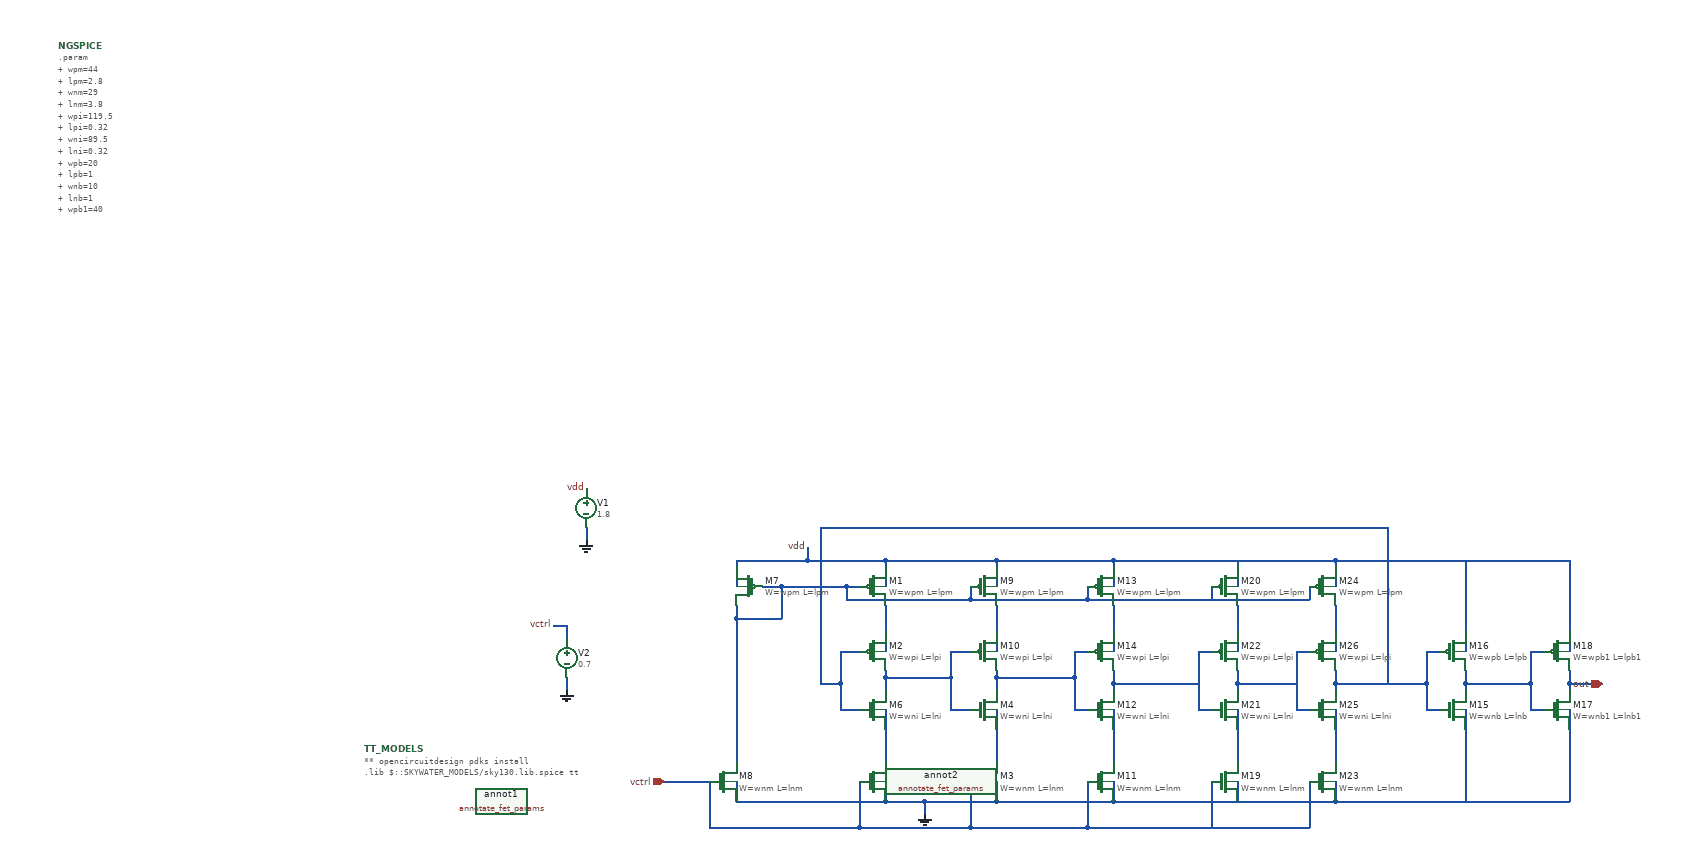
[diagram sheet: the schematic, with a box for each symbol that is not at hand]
v {xschem version=3.4.8RC file_version=1.3}
G {}
K {}
V {}
S {}
F {}
E {}
B 2 770 50 1570 450 {flags=graph
y1=-0.039
y2=1.9
ypos1=0
ypos2=2
divy=5
subdivy=1
unity=1
x1=0
x2=2e-06
divx=5
subdivx=1
xlabmag=1.0
ylabmag=1.0
node=out
color=4
dataset=-1
unitx=1
logx=0
logy=0
hilight_wave=0}
N 480 750 480 770 {lab=#net1}
N 480 640 480 710 {lab=#net2}
N 410 760 410 800 {lab=#net3}
N 410 710 440 710 {lab=#net3}
N 420 610 440 610 {lab=#net4}
N 250 660 320 660 {lab=#net4}
N 320 610 320 660 {lab=#net4}
N 440 910 440 980 {lab=vctrl}
N 210 910 210 980 {lab=vctrl}
N 140 910 210 910 {lab=vctrl}
N 250 910 250 940 {lab=0}
N 250 940 480 940 {lab=0}
N 480 910 480 940 {lab=0}
N 410 800 440 800 {lab=#net3}
N 250 570 250 610 {lab=vdd}
N 360 570 480 570 {lab=vdd}
N 480 570 480 610 {lab=vdd}
N 650 640 650 710 {lab=#net5}
N 610 910 610 980 {lab=vctrl}
N 650 910 650 940 {lab=0}
N 650 570 650 610 {lab=vdd}
N 480 750 580 750 {lab=#net1}
N 580 710 580 750 {lab=#net1}
N 580 710 610 710 {lab=#net1}
N 580 750 580 800 {lab=#net1}
N 580 800 610 800 {lab=#net1}
N 480 570 650 570 {lab=vdd}
N 830 640 830 710 {lab=#net6}
N 790 910 790 980 {lab=vctrl}
N 830 910 830 940 {lab=0}
N 830 570 830 610 {lab=vdd}
N 650 750 770 750 {lab=#net7}
N 770 710 770 750 {lab=#net7}
N 770 710 790 710 {lab=#net7}
N 770 750 770 800 {lab=#net7}
N 770 800 790 800 {lab=#net7}
N 910 760 950 760 {lab=#net8}
N 380 520 380 760 {lab=#net3}
N 380 760 410 760 {lab=#net3}
N 650 940 830 940 {lab=0}
N 610 980 790 980 {lab=vctrl}
N 250 660 250 880 {lab=#net4}
N 360 550 360 570 {lab=vdd}
N 650 570 830 570 {lab=vdd}
N 480 800 480 890 {lab=#net9}
N 20 520 20 540 {lab=0}
N -30 670 -10 670 {lab=vctrl}
N -10 670 -10 690 {lab=vctrl}
N -10 750 -10 770 {lab=0}
N 420 610 420 630 {lab=#net4}
N 420 630 610 630 {lab=#net4}
N 610 610 610 630 {lab=#net4}
N 610 630 790 630 {lab=#net4}
N 790 610 790 630 {lab=#net4}
N 650 750 650 770 {lab=#net7}
N 650 800 650 890 {lab=#net10}
N 830 760 830 770 {lab=#net8}
N 830 800 830 890 {lab=#net11}
N 830 570 1010 570 {lab=vdd}
N 380 520 910 520 {lab=#net3}
N 1010 570 1170 570 {lab=vdd}
N 1010 940 1170 940 {lab=0}
N 250 640 250 660 {lab=#net4}
N 290 610 320 610 {lab=#net4}
N 210 980 440 980 {lab=vctrl}
N 250 570 360 570 {lab=vdd}
N 440 980 610 980 {lab=vctrl}
N 540 940 650 940 {lab=0}
N 480 740 480 750 {lab=#net1}
N 650 740 650 750 {lab=#net7}
N 830 740 830 760 {lab=#net8}
N 410 710 410 760 {lab=#net3}
N 480 940 540 940 {lab=0}
N 320 610 420 610 {lab=#net4}
N 830 760 910 760 {lab=#net8}
N 830 940 1010 940 {lab=0}
N 540 940 540 960 {lab=0}
N 1310 710 1310 760 {lab=#net3}
N 1310 710 1330 710 {lab=#net3}
N 1310 760 1310 800 {lab=#net3}
N 1310 800 1330 800 {lab=#net3}
N 1370 760 1370 770 {lab=#net12}
N 1370 760 1470 760 {lab=#net12}
N 1470 710 1470 760 {lab=#net12}
N 1470 710 1490 710 {lab=#net12}
N 1470 760 1470 800 {lab=#net12}
N 1470 800 1490 800 {lab=#net12}
N 1530 760 1530 770 {lab=out}
N 1530 760 1580 760 {lab=out}
N 1370 740 1370 760 {lab=#net12}
N 1530 740 1530 760 {lab=out}
N 1020 640 1020 710 {lab=#net13}
N 980 910 980 980 {lab=vctrl}
N 1020 910 1020 940 {lab=0}
N 1020 570 1020 610 {lab=vdd}
N 960 710 960 750 {lab=#net8}
N 960 710 980 710 {lab=#net8}
N 960 750 960 800 {lab=#net8}
N 960 800 980 800 {lab=#net8}
N 980 610 980 630 {lab=#net4}
N 1020 760 1020 770 {lab=#net14}
N 1020 800 1020 890 {lab=#net15}
N 1020 740 1020 760 {lab=#net14}
N 1170 640 1170 710 {lab=#net16}
N 1130 910 1130 980 {lab=vctrl}
N 1170 910 1170 940 {lab=0}
N 1170 570 1170 610 {lab=vdd}
N 1110 710 1110 750 {lab=#net14}
N 1110 710 1130 710 {lab=#net14}
N 1110 750 1110 800 {lab=#net14}
N 1110 800 1130 800 {lab=#net14}
N 1130 610 1130 630 {lab=#net4}
N 1170 760 1170 770 {lab=#net3}
N 1170 800 1170 890 {lab=#net17}
N 1170 740 1170 760 {lab=#net3}
N 1170 760 1310 760 {lab=#net3}
N 1170 570 1530 570 {lab=vdd}
N 1530 570 1530 680 {lab=vdd}
N 1370 570 1370 680 {lab=vdd}
N 1370 680 1370 710 {lab=vdd}
N 1530 680 1530 710 {lab=vdd}
N 1370 800 1370 830 {lab=0}
N 1530 800 1530 830 {lab=0}
N 1170 940 1530 940 {lab=0}
N 1530 830 1530 940 {lab=0}
N 1370 830 1370 940 {lab=0}
N 790 980 1130 980 {lab=vctrl}
N 790 630 1130 630 {lab=#net4}
N 950 760 960 760 {lab=#net8}
N 1020 760 1110 760 {lab=#net14}
N 1250 520 1250 760 {lab=#net3}
N 910 520 1250 520 {lab=#net3}
C {sky130_fd_pr/pfet_01v8.sym} 270 610 0 1 {name=M7
W="wpm"
L="lpm"
nf=1
mult=1
ad="expr('int((@nf + 1)/2) * @W / @nf * 0.29')"
pd="expr('2*int((@nf + 1)/2) * (@W / @nf + 0.29)')"
as="expr('int((@nf + 2)/2) * @W / @nf * 0.29')"
ps="expr('2*int((@nf + 2)/2) * (@W / @nf + 0.29)')"
nrd="expr('0.29 / @W ')" nrs="expr('0.29 / @W ')"
sa=0 sb=0 sd=0
model=pfet_01v8
spiceprefix=X
}
C {sky130_fd_pr/nfet_01v8.sym} 230 910 0 0 {name=M8
W="wnm"
L="lnm"
nf=1 
mult=1
ad="expr('int((@nf + 1)/2) * @W / @nf * 0.29')"
pd="expr('2*int((@nf + 1)/2) * (@W / @nf + 0.29)')"
as="expr('int((@nf + 2)/2) * @W / @nf * 0.29')"
ps="expr('2*int((@nf + 2)/2) * (@W / @nf + 0.29)')"
nrd="expr('0.29 / @W ')" nrs="expr('0.29 / @W ')"
sa=0 sb=0 sd=0
model=nfet_01v8
spiceprefix=X
}
C {sky130_fd_pr/nfet_01v8.sym} 460 910 0 0 {name=M5
W="wnm"
L="lnm"
nf=1 
mult=1
ad="expr('int((@nf + 1)/2) * @W / @nf * 0.29')"
pd="expr('2*int((@nf + 1)/2) * (@W / @nf + 0.29)')"
as="expr('int((@nf + 2)/2) * @W / @nf * 0.29')"
ps="expr('2*int((@nf + 2)/2) * (@W / @nf + 0.29)')"
nrd="expr('0.29 / @W ')" nrs="expr('0.29 / @W ')"
sa=0 sb=0 sd=0
model=nfet_01v8
spiceprefix=X
}
C {sky130_fd_pr/nfet_01v8.sym} 460 800 0 0 {name=M6
W="wni"
L="lni"
nf=1 
mult=1
ad="expr('int((@nf + 1)/2) * @W / @nf * 0.29')"
pd="expr('2*int((@nf + 1)/2) * (@W / @nf + 0.29)')"
as="expr('int((@nf + 2)/2) * @W / @nf * 0.29')"
ps="expr('2*int((@nf + 2)/2) * (@W / @nf + 0.29)')"
nrd="expr('0.29 / @W ')" nrs="expr('0.29 / @W ')"
sa=0 sb=0 sd=0
model=nfet_01v8
spiceprefix=X
}
C {sky130_fd_pr/pfet_01v8.sym} 460 610 0 0 {name=M1
W="wpm"
L="lpm"
nf=1
mult=1
ad="expr('int((@nf + 1)/2) * @W / @nf * 0.29')"
pd="expr('2*int((@nf + 1)/2) * (@W / @nf + 0.29)')"
as="expr('int((@nf + 2)/2) * @W / @nf * 0.29')"
ps="expr('2*int((@nf + 2)/2) * (@W / @nf + 0.29)')"
nrd="expr('0.29 / @W ')" nrs="expr('0.29 / @W ')"
sa=0 sb=0 sd=0
model=pfet_01v8
spiceprefix=X
}
C {sky130_fd_pr/pfet_01v8.sym} 460 710 0 0 {name=M2
W="wpi"
L="lpi"
nf=1
mult=1
ad="expr('int((@nf + 1)/2) * @W / @nf * 0.29')"
pd="expr('2*int((@nf + 1)/2) * (@W / @nf + 0.29)')"
as="expr('int((@nf + 2)/2) * @W / @nf * 0.29')"
ps="expr('2*int((@nf + 2)/2) * (@W / @nf + 0.29)')"
nrd="expr('0.29 / @W ')" nrs="expr('0.29 / @W ')"
sa=0 sb=0 sd=0
model=pfet_01v8
spiceprefix=X
}
C {sky130_fd_pr/nfet_01v8.sym} 630 910 0 0 {name=M3
W="wnm"
L="lnm"
nf=1 
mult=1
ad="expr('int((@nf + 1)/2) * @W / @nf * 0.29')"
pd="expr('2*int((@nf + 1)/2) * (@W / @nf + 0.29)')"
as="expr('int((@nf + 2)/2) * @W / @nf * 0.29')"
ps="expr('2*int((@nf + 2)/2) * (@W / @nf + 0.29)')"
nrd="expr('0.29 / @W ')" nrs="expr('0.29 / @W ')"
sa=0 sb=0 sd=0
model=nfet_01v8
spiceprefix=X
}
C {sky130_fd_pr/pfet_01v8.sym} 630 610 0 0 {name=M9
W="wpm"
L="lpm"
nf=1
mult=1
ad="expr('int((@nf + 1)/2) * @W / @nf * 0.29')"
pd="expr('2*int((@nf + 1)/2) * (@W / @nf + 0.29)')"
as="expr('int((@nf + 2)/2) * @W / @nf * 0.29')"
ps="expr('2*int((@nf + 2)/2) * (@W / @nf + 0.29)')"
nrd="expr('0.29 / @W ')" nrs="expr('0.29 / @W ')"
sa=0 sb=0 sd=0
model=pfet_01v8
spiceprefix=X
}
C {sky130_fd_pr/nfet_01v8.sym} 810 910 0 0 {name=M11
W="wnm"
L="lnm"
nf=1 
mult=1
ad="expr('int((@nf + 1)/2) * @W / @nf * 0.29')"
pd="expr('2*int((@nf + 1)/2) * (@W / @nf + 0.29)')"
as="expr('int((@nf + 2)/2) * @W / @nf * 0.29')"
ps="expr('2*int((@nf + 2)/2) * (@W / @nf + 0.29)')"
nrd="expr('0.29 / @W ')" nrs="expr('0.29 / @W ')"
sa=0 sb=0 sd=0
model=nfet_01v8
spiceprefix=X
}
C {sky130_fd_pr/pfet_01v8.sym} 810 610 0 0 {name=M13
W="wpm"
L="lpm"
nf=1
mult=1
ad="expr('int((@nf + 1)/2) * @W / @nf * 0.29')"
pd="expr('2*int((@nf + 1)/2) * (@W / @nf + 0.29)')"
as="expr('int((@nf + 2)/2) * @W / @nf * 0.29')"
ps="expr('2*int((@nf + 2)/2) * (@W / @nf + 0.29)')"
nrd="expr('0.29 / @W ')" nrs="expr('0.29 / @W ')"
sa=0 sb=0 sd=0
model=pfet_01v8
spiceprefix=X
}
C {ipin.sym} 140 910 0 0 {name=p1 lab=vctrl}
C {code_shown.sym} -790 -220 0 0 {name=NGSPICE only_toplevel=false value="
.param
+ wpm=44
+ lpm=2.8
+ wnm=29
+ lnm=3.8
+ wpi=119.5
+ lpi=0.32
+ wni=89.5
+ lni=0.32
+ wpb=20
+ lpb=1
+ wnb=10
+ lnb=1
+ wpb1=40
+ lpb1=1
+ wnb1=20
+ lnb1=1
.control
foreach v_val 0.7 0.8 0.9 1 1.1 1.2
        alter V2 $v_val
        tran 1n 2u
        
        * Measurement logic
        meas tran t_p trig v(out) val=0.9 rise=2 targ v(out) val=0.9 rise=3
        let freq = 1/t_p
        echo For Vctrl = $v_val Frequency = $&freq
    end
.endc
"}
C {gnd.sym} 540 960 0 0 {name=l2 lab=0}
C {vsource.sym} 20 490 0 0 {name=V1 value=1.8 savecurrent=false}
C {lab_pin.sym} 20 460 0 0 {name=p4 sig_type=std_logic lab=vdd}
C {gnd.sym} 20 540 0 0 {name=l3 lab=0}
C {vsource.sym} -10 720 0 0 {name=V2 value=0.7 savecurrent=false}
C {gnd.sym} -10 770 0 0 {name=l4 lab=0}
C {sky130_fd_pr/nfet_01v8.sym} 630 800 0 0 {name=M4
W="wni"
L="lni"
nf=1 
mult=1
ad="expr('int((@nf + 1)/2) * @W / @nf * 0.29')"
pd="expr('2*int((@nf + 1)/2) * (@W / @nf + 0.29)')"
as="expr('int((@nf + 2)/2) * @W / @nf * 0.29')"
ps="expr('2*int((@nf + 2)/2) * (@W / @nf + 0.29)')"
nrd="expr('0.29 / @W ')" nrs="expr('0.29 / @W ')"
sa=0 sb=0 sd=0
model=nfet_01v8
spiceprefix=X
}
C {sky130_fd_pr/pfet_01v8.sym} 630 710 0 0 {name=M10
W="wpi"
L="lpi"
nf=1
mult=1
ad="expr('int((@nf + 1)/2) * @W / @nf * 0.29')"
pd="expr('2*int((@nf + 1)/2) * (@W / @nf + 0.29)')"
as="expr('int((@nf + 2)/2) * @W / @nf * 0.29')"
ps="expr('2*int((@nf + 2)/2) * (@W / @nf + 0.29)')"
nrd="expr('0.29 / @W ')" nrs="expr('0.29 / @W ')"
sa=0 sb=0 sd=0
model=pfet_01v8
spiceprefix=X
}
C {sky130_fd_pr/nfet_01v8.sym} 810 800 0 0 {name=M12
W="wni"
L="lni"
nf=1 
mult=1
ad="expr('int((@nf + 1)/2) * @W / @nf * 0.29')"
pd="expr('2*int((@nf + 1)/2) * (@W / @nf + 0.29)')"
as="expr('int((@nf + 2)/2) * @W / @nf * 0.29')"
ps="expr('2*int((@nf + 2)/2) * (@W / @nf + 0.29)')"
nrd="expr('0.29 / @W ')" nrs="expr('0.29 / @W ')"
sa=0 sb=0 sd=0
model=nfet_01v8
spiceprefix=X
}
C {sky130_fd_pr/pfet_01v8.sym} 810 710 0 0 {name=M14
W="wpi"
L="lpi"
nf=1
mult=1
ad="expr('int((@nf + 1)/2) * @W / @nf * 0.29')"
pd="expr('2*int((@nf + 1)/2) * (@W / @nf + 0.29)')"
as="expr('int((@nf + 2)/2) * @W / @nf * 0.29')"
ps="expr('2*int((@nf + 2)/2) * (@W / @nf + 0.29)')"
nrd="expr('0.29 / @W ')" nrs="expr('0.29 / @W ')"
sa=0 sb=0 sd=0
model=pfet_01v8
spiceprefix=X
}
C {lab_pin.sym} -30 670 0 0 {name=p5 sig_type=std_logic lab=vctrl}
C {lab_pin.sym} 360 550 0 0 {name=p3 sig_type=std_logic lab=vdd}
C {devices/code.sym} -320 860 0 0 {name=TT_MODELS
only_toplevel=true
format="tcleval( @value )"
value="
** opencircuitdesign pdks install
.lib $::SKYWATER_MODELS/sky130.lib.spice tt
"
spice_ignore=false}
C {sky130_fd_pr/annotate_fet_params.sym} -110 940 0 0 {name=annot1 ref=M7}
C {sky130_fd_pr/annotate_fet_params.sym} -20 940 0 0 {name=annot2 ref=M8}
C {launcher.sym} 560 360 0 0 {name=h5
descr="load waves"
tclcommand="xschem raw_read $netlist_dir/vco_5.raw tran"
}
C {iopin.sym} 1580 760 0 0 {name=p2 lab=out}
C {sky130_fd_pr/nfet_01v8.sym} 1350 800 0 0 {name=M15
W="wnb"
L="lnb"
nf=1 
mult=1
ad="expr('int((@nf + 1)/2) * @W / @nf * 0.29')"
pd="expr('2*int((@nf + 1)/2) * (@W / @nf + 0.29)')"
as="expr('int((@nf + 2)/2) * @W / @nf * 0.29')"
ps="expr('2*int((@nf + 2)/2) * (@W / @nf + 0.29)')"
nrd="expr('0.29 / @W ')" nrs="expr('0.29 / @W ')"
sa=0 sb=0 sd=0
model=nfet_01v8
spiceprefix=X
}
C {sky130_fd_pr/pfet_01v8.sym} 1350 710 0 0 {name=M16
W="wpb"
L="lpb"
nf=1
mult=1
ad="expr('int((@nf + 1)/2) * @W / @nf * 0.29')"
pd="expr('2*int((@nf + 1)/2) * (@W / @nf + 0.29)')"
as="expr('int((@nf + 2)/2) * @W / @nf * 0.29')"
ps="expr('2*int((@nf + 2)/2) * (@W / @nf + 0.29)')"
nrd="expr('0.29 / @W ')" nrs="expr('0.29 / @W ')"
sa=0 sb=0 sd=0
model=pfet_01v8
spiceprefix=X
}
C {sky130_fd_pr/nfet_01v8.sym} 1510 800 0 0 {name=M17
W="wnb1"
L="lnb1"
nf=1 
mult=1
ad="expr('int((@nf + 1)/2) * @W / @nf * 0.29')"
pd="expr('2*int((@nf + 1)/2) * (@W / @nf + 0.29)')"
as="expr('int((@nf + 2)/2) * @W / @nf * 0.29')"
ps="expr('2*int((@nf + 2)/2) * (@W / @nf + 0.29)')"
nrd="expr('0.29 / @W ')" nrs="expr('0.29 / @W ')"
sa=0 sb=0 sd=0
model=nfet_01v8
spiceprefix=X
}
C {sky130_fd_pr/pfet_01v8.sym} 1510 710 0 0 {name=M18
W="wpb1"
L="lpb1"
nf=1
mult=1
ad="expr('int((@nf + 1)/2) * @W / @nf * 0.29')"
pd="expr('2*int((@nf + 1)/2) * (@W / @nf + 0.29)')"
as="expr('int((@nf + 2)/2) * @W / @nf * 0.29')"
ps="expr('2*int((@nf + 2)/2) * (@W / @nf + 0.29)')"
nrd="expr('0.29 / @W ')" nrs="expr('0.29 / @W ')"
sa=0 sb=0 sd=0
model=pfet_01v8
spiceprefix=X
}
C {sky130_fd_pr/nfet_01v8.sym} 1000 910 0 0 {name=M19
W="wnm"
L="lnm"
nf=1 
mult=1
ad="expr('int((@nf + 1)/2) * @W / @nf * 0.29')"
pd="expr('2*int((@nf + 1)/2) * (@W / @nf + 0.29)')"
as="expr('int((@nf + 2)/2) * @W / @nf * 0.29')"
ps="expr('2*int((@nf + 2)/2) * (@W / @nf + 0.29)')"
nrd="expr('0.29 / @W ')" nrs="expr('0.29 / @W ')"
sa=0 sb=0 sd=0
model=nfet_01v8
spiceprefix=X
}
C {sky130_fd_pr/pfet_01v8.sym} 1000 610 0 0 {name=M20
W="wpm"
L="lpm"
nf=1
mult=1
ad="expr('int((@nf + 1)/2) * @W / @nf * 0.29')"
pd="expr('2*int((@nf + 1)/2) * (@W / @nf + 0.29)')"
as="expr('int((@nf + 2)/2) * @W / @nf * 0.29')"
ps="expr('2*int((@nf + 2)/2) * (@W / @nf + 0.29)')"
nrd="expr('0.29 / @W ')" nrs="expr('0.29 / @W ')"
sa=0 sb=0 sd=0
model=pfet_01v8
spiceprefix=X
}
C {sky130_fd_pr/nfet_01v8.sym} 1000 800 0 0 {name=M21
W="wni"
L="lni"
nf=1 
mult=1
ad="expr('int((@nf + 1)/2) * @W / @nf * 0.29')"
pd="expr('2*int((@nf + 1)/2) * (@W / @nf + 0.29)')"
as="expr('int((@nf + 2)/2) * @W / @nf * 0.29')"
ps="expr('2*int((@nf + 2)/2) * (@W / @nf + 0.29)')"
nrd="expr('0.29 / @W ')" nrs="expr('0.29 / @W ')"
sa=0 sb=0 sd=0
model=nfet_01v8
spiceprefix=X
}
C {sky130_fd_pr/pfet_01v8.sym} 1000 710 0 0 {name=M22
W="wpi"
L="lpi"
nf=1
mult=1
ad="expr('int((@nf + 1)/2) * @W / @nf * 0.29')"
pd="expr('2*int((@nf + 1)/2) * (@W / @nf + 0.29)')"
as="expr('int((@nf + 2)/2) * @W / @nf * 0.29')"
ps="expr('2*int((@nf + 2)/2) * (@W / @nf + 0.29)')"
nrd="expr('0.29 / @W ')" nrs="expr('0.29 / @W ')"
sa=0 sb=0 sd=0
model=pfet_01v8
spiceprefix=X
}
C {sky130_fd_pr/nfet_01v8.sym} 1150 910 0 0 {name=M23
W="wnm"
L="lnm"
nf=1 
mult=1
ad="expr('int((@nf + 1)/2) * @W / @nf * 0.29')"
pd="expr('2*int((@nf + 1)/2) * (@W / @nf + 0.29)')"
as="expr('int((@nf + 2)/2) * @W / @nf * 0.29')"
ps="expr('2*int((@nf + 2)/2) * (@W / @nf + 0.29)')"
nrd="expr('0.29 / @W ')" nrs="expr('0.29 / @W ')"
sa=0 sb=0 sd=0
model=nfet_01v8
spiceprefix=X
}
C {sky130_fd_pr/pfet_01v8.sym} 1150 610 0 0 {name=M24
W="wpm"
L="lpm"
nf=1
mult=1
ad="expr('int((@nf + 1)/2) * @W / @nf * 0.29')"
pd="expr('2*int((@nf + 1)/2) * (@W / @nf + 0.29)')"
as="expr('int((@nf + 2)/2) * @W / @nf * 0.29')"
ps="expr('2*int((@nf + 2)/2) * (@W / @nf + 0.29)')"
nrd="expr('0.29 / @W ')" nrs="expr('0.29 / @W ')"
sa=0 sb=0 sd=0
model=pfet_01v8
spiceprefix=X
}
C {sky130_fd_pr/nfet_01v8.sym} 1150 800 0 0 {name=M25
W="wni"
L="lni"
nf=1 
mult=1
ad="expr('int((@nf + 1)/2) * @W / @nf * 0.29')"
pd="expr('2*int((@nf + 1)/2) * (@W / @nf + 0.29)')"
as="expr('int((@nf + 2)/2) * @W / @nf * 0.29')"
ps="expr('2*int((@nf + 2)/2) * (@W / @nf + 0.29)')"
nrd="expr('0.29 / @W ')" nrs="expr('0.29 / @W ')"
sa=0 sb=0 sd=0
model=nfet_01v8
spiceprefix=X
}
C {sky130_fd_pr/pfet_01v8.sym} 1150 710 0 0 {name=M26
W="wpi"
L="lpi"
nf=1
mult=1
ad="expr('int((@nf + 1)/2) * @W / @nf * 0.29')"
pd="expr('2*int((@nf + 1)/2) * (@W / @nf + 0.29)')"
as="expr('int((@nf + 2)/2) * @W / @nf * 0.29')"
ps="expr('2*int((@nf + 2)/2) * (@W / @nf + 0.29)')"
nrd="expr('0.29 / @W ')" nrs="expr('0.29 / @W ')"
sa=0 sb=0 sd=0
model=pfet_01v8
spiceprefix=X
}
